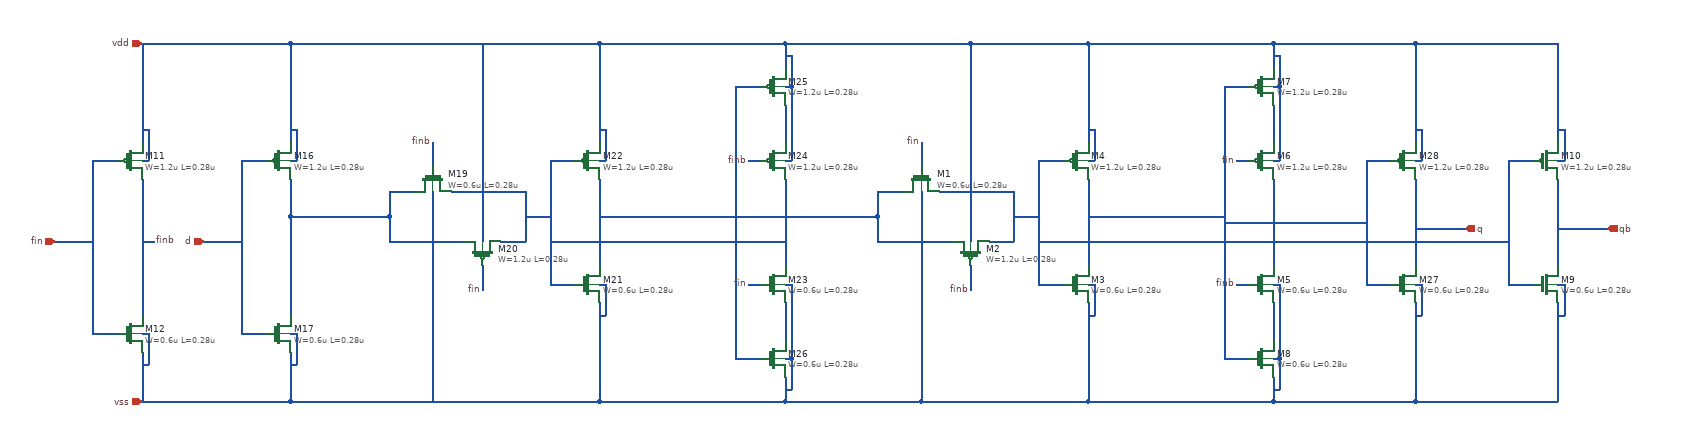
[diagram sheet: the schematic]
v {xschem version=3.4.5 file_version=1.2
}
G {}
K {}
V {}
S {}
E {}
N 460 -520 460 -480 {
lab=vdd}
N 460 -450 470 -450 {
lab=vdd}
N 470 -500 470 -450 {
lab=vdd}
N 460 -500 470 -500 {
lab=vdd}
N 460 -140 460 -100 {
lab=vss}
N 460 -170 470 -170 {
lab=vss}
N 470 -170 470 -120 {
lab=vss}
N 460 -120 470 -120 {
lab=vss}
N 460 -360 620 -360 {
lab=#net1}
N 620 -400 660 -400 {
lab=#net1}
N 620 -400 620 -360 {
lab=#net1}
N 620 -360 620 -320 {
lab=#net1}
N 620 -320 740 -320 {
lab=#net1}
N 720 -400 840 -400 {
lab=#net2}
N 840 -400 840 -320 {
lab=#net2}
N 800 -320 840 -320 {
lab=#net2}
N 770 -280 770 -240 {
lab=fin}
N 690 -480 690 -440 {
lab=finb}
N 690 -400 690 -380 {
lab=vss}
N 770 -340 770 -320 {
lab=vdd}
N 880 -250 920 -250 {
lab=#net2}
N 880 -450 880 -250 {
lab=#net2}
N 880 -450 920 -450 {
lab=#net2}
N 840 -360 880 -360 {
lab=#net2}
N 960 -520 960 -480 {
lab=vdd}
N 960 -450 970 -450 {
lab=vdd}
N 970 -500 970 -450 {
lab=vdd}
N 960 -500 970 -500 {
lab=vdd}
N 960 -220 960 -180 {
lab=vss}
N 960 -250 970 -250 {
lab=vss}
N 970 -250 970 -200 {
lab=vss}
N 960 -200 970 -200 {
lab=vss}
N 960 -420 960 -280 {
lab=#net3}
N 1260 -420 1260 -280 {
lab=#net2}
N 1260 -540 1260 -480 {
lab=#net4}
N 1260 -640 1260 -600 {
lab=vdd}
N 1260 -100 1260 -60 {
lab=vss}
N 1260 -220 1260 -160 {
lab=#net5}
N 1180 -130 1220 -130 {
lab=#net3}
N 1180 -570 1180 -130 {
lab=#net3}
N 1180 -570 1220 -570 {
lab=#net3}
N 1200 -450 1220 -450 {
lab=finb}
N 1200 -250 1220 -250 {
lab=fin}
N 1260 -130 1270 -130 {
lab=vss}
N 1270 -130 1270 -80 {
lab=vss}
N 1260 -80 1270 -80 {
lab=vss}
N 1260 -250 1270 -250 {
lab=vss}
N 1270 -250 1270 -130 {
lab=vss}
N 1260 -570 1270 -570 {
lab=vdd}
N 1270 -620 1270 -570 {
lab=vdd}
N 1260 -620 1270 -620 {
lab=vdd}
N 1260 -450 1270 -450 {
lab=vdd}
N 1270 -570 1270 -450 {
lab=vdd}
N 960 -360 1180 -360 {
lab=#net3}
N 880 -320 1260 -320 {
lab=#net2}
N 2280 -520 2280 -480 {
lab=vdd}
N 2280 -450 2290 -450 {
lab=vdd}
N 2290 -500 2290 -450 {
lab=vdd}
N 2280 -500 2290 -500 {
lab=vdd}
N 2280 -220 2280 -180 {
lab=vss}
N 2280 -250 2290 -250 {
lab=vss}
N 2290 -250 2290 -200 {
lab=vss}
N 2280 -200 2290 -200 {
lab=vss}
N 2280 -420 2280 -280 {
lab=q}
N 2200 -250 2240 -250 {
lab=#net6}
N 2200 -450 2200 -250 {
lab=#net6}
N 2200 -450 2240 -450 {
lab=#net6}
N 960 -640 960 -520 {
lab=vdd}
N 960 -640 1260 -640 {
lab=vdd}
N 1260 -640 1480 -640 {
lab=vdd}
N 2280 -640 2280 -520 {
lab=vdd}
N 1260 -60 1480 -60 {
lab=vss}
N 2280 -180 2280 -60 {
lab=vss}
N 960 -180 960 -60 {
lab=vss}
N 960 -60 1260 -60 {
lab=vss}
N 460 -100 460 -60 {
lab=vss}
N 460 -60 960 -60 {
lab=vss}
N 460 -640 960 -640 {
lab=vdd}
N 690 -380 690 -60 {
lab=vss}
N 770 -640 770 -340 {
lab=vdd}
N 460 -240 460 -200 {
lab=#net1}
N 460 -360 460 -240 {
lab=#net1}
N 380 -170 420 -170 {
lab=d}
N 2280 -340 2360 -340 {
lab=q}
N 460 -640 460 -520 {
lab=vdd}
N 460 -420 460 -360 {
lab=#net1}
N 380 -450 420 -450 {
lab=d}
N 380 -450 380 -170 {
lab=d}
N 320 -320 380 -320 {
lab=d}
N 1410 -400 1450 -400 {
lab=#net3}
N 1410 -400 1410 -360 {
lab=#net3}
N 1410 -360 1410 -320 {
lab=#net3}
N 1410 -320 1530 -320 {
lab=#net3}
N 1510 -400 1630 -400 {
lab=#net7}
N 1630 -400 1630 -320 {
lab=#net7}
N 1590 -320 1630 -320 {
lab=#net7}
N 1560 -280 1560 -240 {
lab=finb}
N 1480 -480 1480 -440 {
lab=fin}
N 1480 -400 1480 -380 {
lab=vss}
N 1560 -340 1560 -320 {
lab=vdd}
N 1670 -250 1710 -250 {
lab=#net7}
N 1670 -450 1670 -250 {
lab=#net7}
N 1670 -450 1710 -450 {
lab=#net7}
N 1630 -360 1670 -360 {
lab=#net7}
N 1750 -520 1750 -480 {
lab=vdd}
N 1750 -450 1760 -450 {
lab=vdd}
N 1760 -500 1760 -450 {
lab=vdd}
N 1750 -500 1760 -500 {
lab=vdd}
N 1750 -220 1750 -180 {
lab=vss}
N 1750 -250 1760 -250 {
lab=vss}
N 1760 -250 1760 -200 {
lab=vss}
N 1750 -200 1760 -200 {
lab=vss}
N 1750 -420 1750 -280 {
lab=#net6}
N 2050 -420 2050 -280 {
lab=#net7}
N 2050 -540 2050 -480 {
lab=#net8}
N 2050 -640 2050 -600 {
lab=vdd}
N 2050 -100 2050 -60 {
lab=vss}
N 2050 -220 2050 -160 {
lab=#net9}
N 1970 -130 2010 -130 {
lab=#net6}
N 1970 -570 1970 -130 {
lab=#net6}
N 1970 -570 2010 -570 {
lab=#net6}
N 1990 -450 2010 -450 {
lab=fin}
N 1990 -250 2010 -250 {
lab=finb}
N 2050 -130 2060 -130 {
lab=vss}
N 2060 -130 2060 -80 {
lab=vss}
N 2050 -80 2060 -80 {
lab=vss}
N 2050 -250 2060 -250 {
lab=vss}
N 2060 -250 2060 -130 {
lab=vss}
N 2050 -570 2060 -570 {
lab=vdd}
N 2060 -620 2060 -570 {
lab=vdd}
N 2050 -620 2060 -620 {
lab=vdd}
N 2050 -450 2060 -450 {
lab=vdd}
N 2060 -570 2060 -450 {
lab=vdd}
N 1750 -360 1970 -360 {
lab=#net6}
N 1670 -320 2050 -320 {
lab=#net7}
N 1750 -640 1750 -520 {
lab=vdd}
N 1750 -640 2050 -640 {
lab=vdd}
N 1750 -180 1750 -60 {
lab=vss}
N 1750 -60 2050 -60 {
lab=vss}
N 1480 -380 1480 -60 {
lab=vss}
N 1560 -640 1560 -340 {
lab=vdd}
N 1180 -360 1410 -360 {
lab=#net3}
N 1480 -640 1560 -640 {
lab=vdd}
N 1560 -640 1750 -640 {
lab=vdd}
N 1480 -60 1750 -60 {
lab=vss}
N 2050 -60 2280 -60 {
lab=vss}
N 2050 -640 2280 -640 {
lab=vdd}
N 1970 -350 2200 -350 {
lab=#net6}
N 2510 -520 2510 -480 {
lab=vdd}
N 2510 -450 2520 -450 {
lab=vdd}
N 2520 -500 2520 -450 {
lab=vdd}
N 2510 -500 2520 -500 {
lab=vdd}
N 2510 -220 2510 -180 {
lab=vss}
N 2510 -250 2520 -250 {
lab=vss}
N 2520 -250 2520 -200 {
lab=vss}
N 2510 -200 2520 -200 {
lab=vss}
N 2510 -420 2510 -280 {
lab=qb}
N 2430 -250 2470 -250 {
lab=#net7}
N 2430 -450 2430 -250 {
lab=#net7}
N 2430 -450 2470 -450 {
lab=#net7}
N 2510 -640 2510 -520 {
lab=vdd}
N 2510 -180 2510 -60 {
lab=vss}
N 2510 -340 2590 -340 {
lab=qb}
N 2280 -60 2510 -60 {
lab=vss}
N 2280 -640 2510 -640 {
lab=vdd}
N 2050 -320 2430 -320 {
lab=#net7}
N 220 -520 220 -480 {
lab=vdd}
N 220 -450 230 -450 {
lab=vdd}
N 230 -500 230 -450 {
lab=vdd}
N 220 -500 230 -500 {
lab=vdd}
N 220 -140 220 -100 {
lab=vss}
N 220 -170 230 -170 {
lab=vss}
N 230 -170 230 -120 {
lab=vss}
N 220 -120 230 -120 {
lab=vss}
N 220 -100 220 -60 {
lab=vss}
N 220 -240 220 -200 {
lab=#net10}
N 220 -360 220 -240 {
lab=#net10}
N 140 -170 180 -170 {
lab=fin}
N 220 -640 220 -520 {
lab=vdd}
N 220 -420 220 -360 {
lab=#net10}
N 140 -450 180 -450 {
lab=fin}
N 140 -450 140 -170 {
lab=fin}
N 80 -320 140 -320 {
lab=fin}
N 220 -60 460 -60 {
lab=vss}
N 220 -640 460 -640 {
lab=vdd}
N 220 -320 240 -320 {
lab=#net10}
C {symbols/pfet_03v3.sym} 440 -450 0 0 {name=M16
L=0.28u
W=1.2u
nf=1
m=1
ad="'int((nf+1)/2) * W/nf * 0.18u'"
pd="'2*int((nf+1)/2) * (W/nf + 0.18u)'"
as="'int((nf+2)/2) * W/nf * 0.18u'"
ps="'2*int((nf+2)/2) * (W/nf + 0.18u)'"
nrd="'0.18u / W'" nrs="'0.18u / W'"
sa=0 sb=0 sd=0
model=pfet_03v3
spiceprefix=X
}
C {symbols/nfet_03v3.sym} 440 -170 0 0 {name=M17
L=0.28u
W=0.6u
nf=1
m=1
ad="'int((nf+1)/2) * W/nf * 0.18u'"
pd="'2*int((nf+1)/2) * (W/nf + 0.18u)'"
as="'int((nf+2)/2) * W/nf * 0.18u'"
ps="'2*int((nf+2)/2) * (W/nf + 0.18u)'"
nrd="'0.18u / W'" nrs="'0.18u / W'"
sa=0 sb=0 sd=0
model=nfet_03v3
spiceprefix=X
}
C {symbols/nfet_03v3.sym} 690 -420 1 0 {name=M19
L=0.28u
W=0.6u
nf=1
m=1
ad="'int((nf+1)/2) * W/nf * 0.18u'"
pd="'2*int((nf+1)/2) * (W/nf + 0.18u)'"
as="'int((nf+2)/2) * W/nf * 0.18u'"
ps="'2*int((nf+2)/2) * (W/nf + 0.18u)'"
nrd="'0.18u / W'" nrs="'0.18u / W'"
sa=0 sb=0 sd=0
model=nfet_03v3
spiceprefix=X
}
C {symbols/pfet_03v3.sym} 770 -300 3 0 {name=M20
L=0.28u
W=1.2u
nf=1
m=1
ad="'int((nf+1)/2) * W/nf * 0.18u'"
pd="'2*int((nf+1)/2) * (W/nf + 0.18u)'"
as="'int((nf+2)/2) * W/nf * 0.18u'"
ps="'2*int((nf+2)/2) * (W/nf + 0.18u)'"
nrd="'0.18u / W'" nrs="'0.18u / W'"
sa=0 sb=0 sd=0
model=pfet_03v3
spiceprefix=X
}
C {symbols/nfet_03v3.sym} 940 -250 0 0 {name=M21
L=0.28u
W=0.6u
nf=1
m=1
ad="'int((nf+1)/2) * W/nf * 0.18u'"
pd="'2*int((nf+1)/2) * (W/nf + 0.18u)'"
as="'int((nf+2)/2) * W/nf * 0.18u'"
ps="'2*int((nf+2)/2) * (W/nf + 0.18u)'"
nrd="'0.18u / W'" nrs="'0.18u / W'"
sa=0 sb=0 sd=0
model=nfet_03v3
spiceprefix=X
}
C {symbols/pfet_03v3.sym} 940 -450 0 0 {name=M22
L=0.28u
W=1.2u
nf=1
m=1
ad="'int((nf+1)/2) * W/nf * 0.18u'"
pd="'2*int((nf+1)/2) * (W/nf + 0.18u)'"
as="'int((nf+2)/2) * W/nf * 0.18u'"
ps="'2*int((nf+2)/2) * (W/nf + 0.18u)'"
nrd="'0.18u / W'" nrs="'0.18u / W'"
sa=0 sb=0 sd=0
model=pfet_03v3
spiceprefix=X
}
C {symbols/nfet_03v3.sym} 1240 -250 0 0 {name=M23
L=0.28u
W=0.6u
nf=1
m=1
ad="'int((nf+1)/2) * W/nf * 0.18u'"
pd="'2*int((nf+1)/2) * (W/nf + 0.18u)'"
as="'int((nf+2)/2) * W/nf * 0.18u'"
ps="'2*int((nf+2)/2) * (W/nf + 0.18u)'"
nrd="'0.18u / W'" nrs="'0.18u / W'"
sa=0 sb=0 sd=0
model=nfet_03v3
spiceprefix=X
}
C {symbols/pfet_03v3.sym} 1240 -450 0 0 {name=M24
L=0.28u
W=1.2u
nf=1
m=1
ad="'int((nf+1)/2) * W/nf * 0.18u'"
pd="'2*int((nf+1)/2) * (W/nf + 0.18u)'"
as="'int((nf+2)/2) * W/nf * 0.18u'"
ps="'2*int((nf+2)/2) * (W/nf + 0.18u)'"
nrd="'0.18u / W'" nrs="'0.18u / W'"
sa=0 sb=0 sd=0
model=pfet_03v3
spiceprefix=X
}
C {symbols/pfet_03v3.sym} 1240 -570 0 0 {name=M25
L=0.28u
W=1.2u
nf=1
m=1
ad="'int((nf+1)/2) * W/nf * 0.18u'"
pd="'2*int((nf+1)/2) * (W/nf + 0.18u)'"
as="'int((nf+2)/2) * W/nf * 0.18u'"
ps="'2*int((nf+2)/2) * (W/nf + 0.18u)'"
nrd="'0.18u / W'" nrs="'0.18u / W'"
sa=0 sb=0 sd=0
model=pfet_03v3
spiceprefix=X
}
C {symbols/nfet_03v3.sym} 1240 -130 0 0 {name=M26
L=0.28u
W=0.6u
nf=1
m=1
ad="'int((nf+1)/2) * W/nf * 0.18u'"
pd="'2*int((nf+1)/2) * (W/nf + 0.18u)'"
as="'int((nf+2)/2) * W/nf * 0.18u'"
ps="'2*int((nf+2)/2) * (W/nf + 0.18u)'"
nrd="'0.18u / W'" nrs="'0.18u / W'"
sa=0 sb=0 sd=0
model=nfet_03v3
spiceprefix=X
}
C {symbols/nfet_03v3.sym} 2260 -250 0 0 {name=M27
L=0.28u
W=0.6u
nf=1
m=1
ad="'int((nf+1)/2) * W/nf * 0.18u'"
pd="'2*int((nf+1)/2) * (W/nf + 0.18u)'"
as="'int((nf+2)/2) * W/nf * 0.18u'"
ps="'2*int((nf+2)/2) * (W/nf + 0.18u)'"
nrd="'0.18u / W'" nrs="'0.18u / W'"
sa=0 sb=0 sd=0
model=nfet_03v3
spiceprefix=X
}
C {symbols/pfet_03v3.sym} 2260 -450 0 0 {name=M28
L=0.28u
W=1.2u
nf=1
m=1
ad="'int((nf+1)/2) * W/nf * 0.18u'"
pd="'2*int((nf+1)/2) * (W/nf + 0.18u)'"
as="'int((nf+2)/2) * W/nf * 0.18u'"
ps="'2*int((nf+2)/2) * (W/nf + 0.18u)'"
nrd="'0.18u / W'" nrs="'0.18u / W'"
sa=0 sb=0 sd=0
model=pfet_03v3
spiceprefix=X
}
C {lab_pin.sym} 770 -240 1 1 {name=p16 sig_type=std_logic lab=fin}
C {lab_pin.sym} 1200 -250 2 1 {name=p17 sig_type=std_logic lab=fin}
C {lab_pin.sym} 1200 -450 2 1 {name=p18 sig_type=std_logic lab=finb}
C {lab_pin.sym} 690 -480 3 1 {name=p19 sig_type=std_logic lab=finb}
C {symbols/nfet_03v3.sym} 1480 -420 1 0 {name=M1
L=0.28u
W=0.6u
nf=1
m=1
ad="'int((nf+1)/2) * W/nf * 0.18u'"
pd="'2*int((nf+1)/2) * (W/nf + 0.18u)'"
as="'int((nf+2)/2) * W/nf * 0.18u'"
ps="'2*int((nf+2)/2) * (W/nf + 0.18u)'"
nrd="'0.18u / W'" nrs="'0.18u / W'"
sa=0 sb=0 sd=0
model=nfet_03v3
spiceprefix=X
}
C {symbols/pfet_03v3.sym} 1560 -300 3 0 {name=M2
L=0.28u
W=1.2u
nf=1
m=1
ad="'int((nf+1)/2) * W/nf * 0.18u'"
pd="'2*int((nf+1)/2) * (W/nf + 0.18u)'"
as="'int((nf+2)/2) * W/nf * 0.18u'"
ps="'2*int((nf+2)/2) * (W/nf + 0.18u)'"
nrd="'0.18u / W'" nrs="'0.18u / W'"
sa=0 sb=0 sd=0
model=pfet_03v3
spiceprefix=X
}
C {symbols/nfet_03v3.sym} 1730 -250 0 0 {name=M3
L=0.28u
W=0.6u
nf=1
m=1
ad="'int((nf+1)/2) * W/nf * 0.18u'"
pd="'2*int((nf+1)/2) * (W/nf + 0.18u)'"
as="'int((nf+2)/2) * W/nf * 0.18u'"
ps="'2*int((nf+2)/2) * (W/nf + 0.18u)'"
nrd="'0.18u / W'" nrs="'0.18u / W'"
sa=0 sb=0 sd=0
model=nfet_03v3
spiceprefix=X
}
C {symbols/pfet_03v3.sym} 1730 -450 0 0 {name=M4
L=0.28u
W=1.2u
nf=1
m=1
ad="'int((nf+1)/2) * W/nf * 0.18u'"
pd="'2*int((nf+1)/2) * (W/nf + 0.18u)'"
as="'int((nf+2)/2) * W/nf * 0.18u'"
ps="'2*int((nf+2)/2) * (W/nf + 0.18u)'"
nrd="'0.18u / W'" nrs="'0.18u / W'"
sa=0 sb=0 sd=0
model=pfet_03v3
spiceprefix=X
}
C {symbols/nfet_03v3.sym} 2030 -250 0 0 {name=M5
L=0.28u
W=0.6u
nf=1
m=1
ad="'int((nf+1)/2) * W/nf * 0.18u'"
pd="'2*int((nf+1)/2) * (W/nf + 0.18u)'"
as="'int((nf+2)/2) * W/nf * 0.18u'"
ps="'2*int((nf+2)/2) * (W/nf + 0.18u)'"
nrd="'0.18u / W'" nrs="'0.18u / W'"
sa=0 sb=0 sd=0
model=nfet_03v3
spiceprefix=X
}
C {symbols/pfet_03v3.sym} 2030 -450 0 0 {name=M6
L=0.28u
W=1.2u
nf=1
m=1
ad="'int((nf+1)/2) * W/nf * 0.18u'"
pd="'2*int((nf+1)/2) * (W/nf + 0.18u)'"
as="'int((nf+2)/2) * W/nf * 0.18u'"
ps="'2*int((nf+2)/2) * (W/nf + 0.18u)'"
nrd="'0.18u / W'" nrs="'0.18u / W'"
sa=0 sb=0 sd=0
model=pfet_03v3
spiceprefix=X
}
C {symbols/pfet_03v3.sym} 2030 -570 0 0 {name=M7
L=0.28u
W=1.2u
nf=1
m=1
ad="'int((nf+1)/2) * W/nf * 0.18u'"
pd="'2*int((nf+1)/2) * (W/nf + 0.18u)'"
as="'int((nf+2)/2) * W/nf * 0.18u'"
ps="'2*int((nf+2)/2) * (W/nf + 0.18u)'"
nrd="'0.18u / W'" nrs="'0.18u / W'"
sa=0 sb=0 sd=0
model=pfet_03v3
spiceprefix=X
}
C {symbols/nfet_03v3.sym} 2030 -130 0 0 {name=M8
L=0.28u
W=0.6u
nf=1
m=1
ad="'int((nf+1)/2) * W/nf * 0.18u'"
pd="'2*int((nf+1)/2) * (W/nf + 0.18u)'"
as="'int((nf+2)/2) * W/nf * 0.18u'"
ps="'2*int((nf+2)/2) * (W/nf + 0.18u)'"
nrd="'0.18u / W'" nrs="'0.18u / W'"
sa=0 sb=0 sd=0
model=nfet_03v3
spiceprefix=X
}
C {lab_pin.sym} 1480 -480 3 1 {name=p1 sig_type=std_logic lab=fin}
C {lab_pin.sym} 1990 -450 2 1 {name=p2 sig_type=std_logic lab=fin}
C {lab_pin.sym} 1990 -250 2 1 {name=p3 sig_type=std_logic lab=finb}
C {lab_pin.sym} 1560 -240 1 1 {name=p4 sig_type=std_logic lab=finb}
C {symbols/nfet_03v3.sym} 2490 -250 0 0 {name=M9
L=0.28u
W=0.6u
nf=1
m=1
ad="'int((nf+1)/2) * W/nf * 0.18u'"
pd="'2*int((nf+1)/2) * (W/nf + 0.18u)'"
as="'int((nf+2)/2) * W/nf * 0.18u'"
ps="'2*int((nf+2)/2) * (W/nf + 0.18u)'"
nrd="'0.18u / W'" nrs="'0.18u / W'"
sa=0 sb=0 sd=0
model=nfet_03v3
spiceprefix=X
}
C {symbols/pfet_03v3.sym} 2490 -450 0 0 {name=M10
L=0.28u
W=1.2u
nf=1
m=1
ad="'int((nf+1)/2) * W/nf * 0.18u'"
pd="'2*int((nf+1)/2) * (W/nf + 0.18u)'"
as="'int((nf+2)/2) * W/nf * 0.18u'"
ps="'2*int((nf+2)/2) * (W/nf + 0.18u)'"
nrd="'0.18u / W'" nrs="'0.18u / W'"
sa=0 sb=0 sd=0
model=pfet_03v3
spiceprefix=X
}
C {opin.sym} 2360 -340 0 0 {name=p5 lab=q}
C {opin.sym} 2590 -340 0 0 {name=p6 lab=qb}
C {ipin.sym} 320 -320 0 0 {name=p7 lab=d}
C {ipin.sym} 220 -640 0 0 {name=p8 lab=vdd}
C {ipin.sym} 220 -60 0 0 {name=p9 lab=vss}
C {ipin.sym} 80 -320 0 0 {name=p10 lab=fin}
C {symbols/pfet_03v3.sym} 200 -450 0 0 {name=M11
L=0.28u
W=1.2u
nf=1
m=1
ad="'int((nf+1)/2) * W/nf * 0.18u'"
pd="'2*int((nf+1)/2) * (W/nf + 0.18u)'"
as="'int((nf+2)/2) * W/nf * 0.18u'"
ps="'2*int((nf+2)/2) * (W/nf + 0.18u)'"
nrd="'0.18u / W'" nrs="'0.18u / W'"
sa=0 sb=0 sd=0
model=pfet_03v3
spiceprefix=X
}
C {symbols/nfet_03v3.sym} 200 -170 0 0 {name=M12
L=0.28u
W=0.6u
nf=1
m=1
ad="'int((nf+1)/2) * W/nf * 0.18u'"
pd="'2*int((nf+1)/2) * (W/nf + 0.18u)'"
as="'int((nf+2)/2) * W/nf * 0.18u'"
ps="'2*int((nf+2)/2) * (W/nf + 0.18u)'"
nrd="'0.18u / W'" nrs="'0.18u / W'"
sa=0 sb=0 sd=0
model=nfet_03v3
spiceprefix=X
}
C {lab_pin.sym} 240 -320 0 1 {name=p11 sig_type=std_logic lab=finb}
